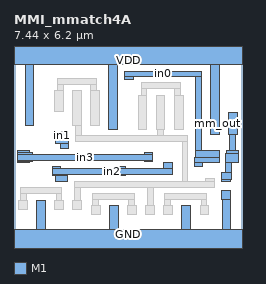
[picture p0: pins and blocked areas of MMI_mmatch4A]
MACRO MMI_mmatch4A
	CLASS CORE ;
	FOREIGN MMI_mmatch4A 0 0 ;
	SIZE 7.44 BY 6.2 ;
	SYMMETRY X Y ;
	SITE CORE1 ;
	PIN in1
		DIRECTION input ;
		USE SIGNAL ;
		PORT
			LAYER M1 ;
			RECT 1.36 3.345 1.74 3.6 ;
			LAYER M1 ;
			RECT 1.36 3.22 1.785 3.345 ;
			LAYER M1 ;
			RECT 1.505 3.065 1.785 3.22 ;
		END
		AntennaGateArea 0.4755 ;
	END in1
	PIN GND
		DIRECTION inout ;
		USE GROUND ;
		PORT
			LAYER M1 ;
			RECT 6.76 1.395 7.075 1.675 ;
			LAYER M1 ;
			RECT 0.745 0.42 1.025 1.36 ;
			LAYER M1 ;
			RECT 3.12 0.42 3.4 1.2 ;
			LAYER M1 ;
			RECT 5.48 0.42 5.76 1.2 ;
			LAYER M1 ;
			RECT 6.795 0.42 7.075 1.395 ;
			LAYER M1 ;
			RECT 0 -0.42 7.44 0.42 ;
		END
	END GND
	PIN mm_out
		DIRECTION output ;
		USE SIGNAL ;
		PORT
			LAYER M1 ;
			RECT 7.005 3.52 7.285 4.22 ;
			LAYER M1 ;
			RECT 7.03 2.98 7.22 3.52 ;
			LAYER M1 ;
			RECT 6.94 2.89 7.32 2.98 ;
			LAYER M1 ;
			RECT 6.9 2.6 7.32 2.89 ;
			LAYER M1 ;
			RECT 6.9 2.265 7.09 2.6 ;
			LAYER M1 ;
			RECT 6.76 2.05 7.09 2.265 ;
			LAYER M1 ;
			RECT 6.76 1.985 7.075 2.05 ;
		END
		AntennaDiffArea 0.456225 ;
	END mm_out
	PIN in2
		DIRECTION input ;
		USE SIGNAL ;
		PORT
			LAYER M1 ;
			RECT 1.24 2.39 1.52 2.45 ;
			LAYER M1 ;
			RECT 3.355 2.39 3.635 2.465 ;
			LAYER M1 ;
			RECT 4.885 2.39 5.165 2.605 ;
			LAYER M1 ;
			RECT 1.24 2.2 5.165 2.39 ;
			LAYER M1 ;
			RECT 1.24 2.17 1.74 2.2 ;
			LAYER M1 ;
			RECT 3.355 2.185 3.635 2.2 ;
			LAYER M1 ;
			RECT 1.36 1.98 1.74 2.17 ;
		END
		AntennaGateArea 0.53325 ;
	END in2
	PIN VDD
		DIRECTION inout ;
		USE POWER ;
		PORT
			LAYER M1 ;
			RECT 0 5.78 7.44 6.62 ;
			LAYER M1 ;
			RECT 0.365 3.81 0.645 5.78 ;
			LAYER M1 ;
			RECT 3.095 3.66 3.375 5.78 ;
			LAYER M1 ;
			RECT 6.415 3.52 6.695 5.78 ;
		END
	END VDD
	PIN in3
		DIRECTION input ;
		USE SIGNAL ;
		PORT
			LAYER M1 ;
			RECT 0.12 2.905 0.5 2.98 ;
			LAYER M1 ;
			RECT 0.12 2.865 0.615 2.905 ;
			LAYER M1 ;
			RECT 4.245 2.865 4.525 2.905 ;
			LAYER M1 ;
			RECT 0.12 2.675 4.525 2.865 ;
			LAYER M1 ;
			RECT 0.12 2.625 0.615 2.675 ;
			LAYER M1 ;
			RECT 4.245 2.625 4.525 2.675 ;
			LAYER M1 ;
			RECT 0.12 2.6 0.5 2.625 ;
		END
		AntennaGateArea 0.4755 ;
	END in3
	PIN in0
		DIRECTION input ;
		USE SIGNAL ;
		PORT
			LAYER M1 ;
			RECT 3.605 5.39 6.125 5.58 ;
			LAYER M1 ;
			RECT 3.605 5.3 3.885 5.39 ;
			LAYER M1 ;
			RECT 5.935 2.98 6.125 5.39 ;
			LAYER M1 ;
			RECT 5.935 2.76 6.7 2.98 ;
			LAYER M1 ;
			RECT 5.875 2.6 6.7 2.76 ;
			LAYER M1 ;
			RECT 5.875 2.48 6.155 2.6 ;
		END
		AntennaGateArea 0.4755 ;
	END in0
	OBS
		LAYER M1 ;
		RECT 1.415 5.14 2.695 5.33 ;
		LAYER M1 ;
		RECT 1.415 4.94 1.605 5.14 ;
		LAYER M1 ;
		RECT 2.505 4.94 2.695 5.14 ;
		LAYER M1 ;
		RECT 1.325 4.27 1.605 4.94 ;
		LAYER M1 ;
		RECT 1.915 3.81 2.195 4.94 ;
		LAYER M1 ;
		RECT 2.505 3.81 2.785 4.94 ;
		LAYER M1 ;
		RECT 2 3.46 2.19 3.81 ;
		LAYER M1 ;
		RECT 4.145 5 5.425 5.19 ;
		LAYER M1 ;
		RECT 4.145 4.79 4.335 5 ;
		LAYER M1 ;
		RECT 5.235 4.79 5.425 5 ;
		LAYER M1 ;
		RECT 4.055 3.66 4.335 4.79 ;
		LAYER M1 ;
		RECT 4.645 3.66 4.925 4.79 ;
		LAYER M1 ;
		RECT 5.235 3.66 5.515 4.79 ;
		LAYER M1 ;
		RECT 4.685 3.46 4.875 3.66 ;
		LAYER M1 ;
		RECT 2 3.27 5.675 3.46 ;
		LAYER M1 ;
		RECT 5.485 1.98 5.675 3.27 ;
		LAYER M1 ;
		RECT 6.255 1.98 6.535 2.07 ;
		LAYER M1 ;
		RECT 1.965 1.79 6.535 1.98 ;
		LAYER M1 ;
		RECT 0.215 1.58 1.565 1.77 ;
		LAYER M1 ;
		RECT 0.215 1.36 0.405 1.58 ;
		LAYER M1 ;
		RECT 1.375 1.36 1.565 1.58 ;
		LAYER M1 ;
		RECT 1.965 1.36 2.155 1.79 ;
		LAYER M1 ;
		RECT 2.57 1.4 3.94 1.59 ;
		LAYER M1 ;
		RECT 0.155 1.045 0.435 1.36 ;
		LAYER M1 ;
		RECT 1.335 1.045 1.615 1.36 ;
		LAYER M1 ;
		RECT 1.925 1.045 2.205 1.36 ;
		LAYER M1 ;
		RECT 2.57 1.2 2.76 1.4 ;
		LAYER M1 ;
		RECT 3.75 1.2 3.94 1.4 ;
		LAYER M1 ;
		RECT 4.35 1.2 4.54 1.79 ;
		LAYER M1 ;
		RECT 4.925 1.4 6.295 1.59 ;
		LAYER M1 ;
		RECT 4.925 1.2 5.115 1.4 ;
		LAYER M1 ;
		RECT 6.105 1.2 6.295 1.4 ;
		LAYER M1 ;
		RECT 2.53 0.885 2.81 1.2 ;
		LAYER M1 ;
		RECT 3.71 0.885 3.99 1.2 ;
		LAYER M1 ;
		RECT 4.3 0.885 4.58 1.2 ;
		LAYER M1 ;
		RECT 4.89 0.885 5.17 1.2 ;
		LAYER M1 ;
		RECT 6.07 0.885 6.35 1.2 ;
	END
END MMI_mmatch4A
